VERSION 5.8 ;
BUSBITCHARS "[]" ;
DIVIDERCHAR "/" ;
UNITS
    DATABASE MICRONS 1000 ;
END UNITS

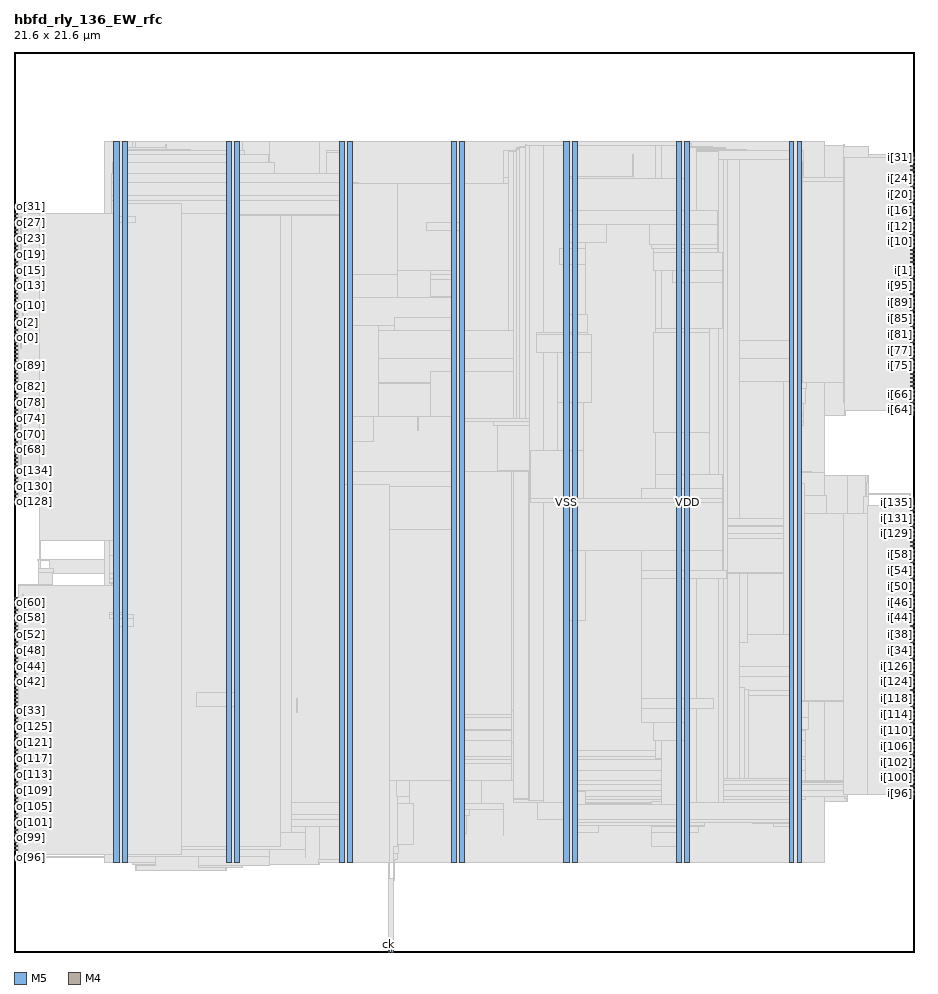
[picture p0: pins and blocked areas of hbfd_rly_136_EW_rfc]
MACRO hbfd_rly_136_EW_rfc
  FOREIGN hbfd_rly_136_EW_rfc 0 0 ;
  CLASS BLOCK ;
  SIZE 21.6 BY 21.6 ;
  PIN ck
    DIRECTION INPUT ;
    USE SIGNAL ;
    PORT
      LAYER M5 ;
        RECT  8.976 0 9 0.084 ;
    END
  END ck
  PIN i[0]
    DIRECTION INPUT ;
    USE SIGNAL ;
    PORT
      LAYER M4 ;
        RECT  21.516 16.08 21.6 16.104 ;
    END
  END i[0]
  PIN i[100]
    DIRECTION INPUT ;
    USE SIGNAL ;
    PORT
      LAYER M4 ;
        RECT  21.516 4.176 21.6 4.2 ;
    END
  END i[100]
  PIN i[101]
    DIRECTION INPUT ;
    USE SIGNAL ;
    PORT
      LAYER M4 ;
        RECT  21.516 4.272 21.6 4.296 ;
    END
  END i[101]
  PIN i[102]
    DIRECTION INPUT ;
    USE SIGNAL ;
    PORT
      LAYER M4 ;
        RECT  21.516 4.368 21.6 4.392 ;
    END
  END i[102]
  PIN i[103]
    DIRECTION INPUT ;
    USE SIGNAL ;
    PORT
      LAYER M4 ;
        RECT  21.516 4.464 21.6 4.488 ;
    END
  END i[103]
  PIN i[104]
    DIRECTION INPUT ;
    USE SIGNAL ;
    PORT
      LAYER M4 ;
        RECT  21.516 4.56 21.6 4.584 ;
    END
  END i[104]
  PIN i[105]
    DIRECTION INPUT ;
    USE SIGNAL ;
    PORT
      LAYER M4 ;
        RECT  21.516 4.656 21.6 4.68 ;
    END
  END i[105]
  PIN i[106]
    DIRECTION INPUT ;
    USE SIGNAL ;
    PORT
      LAYER M4 ;
        RECT  21.516 4.752 21.6 4.776 ;
    END
  END i[106]
  PIN i[107]
    DIRECTION INPUT ;
    USE SIGNAL ;
    PORT
      LAYER M4 ;
        RECT  21.516 4.848 21.6 4.872 ;
    END
  END i[107]
  PIN i[108]
    DIRECTION INPUT ;
    USE SIGNAL ;
    PORT
      LAYER M4 ;
        RECT  21.516 4.944 21.6 4.968 ;
    END
  END i[108]
  PIN i[109]
    DIRECTION INPUT ;
    USE SIGNAL ;
    PORT
      LAYER M4 ;
        RECT  21.516 5.04 21.6 5.064 ;
    END
  END i[109]
  PIN i[10]
    DIRECTION INPUT ;
    USE SIGNAL ;
    PORT
      LAYER M4 ;
        RECT  21.516 17.04 21.6 17.064 ;
    END
  END i[10]
  PIN i[110]
    DIRECTION INPUT ;
    USE SIGNAL ;
    PORT
      LAYER M4 ;
        RECT  21.516 5.136 21.6 5.16 ;
    END
  END i[110]
  PIN i[111]
    DIRECTION INPUT ;
    USE SIGNAL ;
    PORT
      LAYER M4 ;
        RECT  21.516 5.232 21.6 5.256 ;
    END
  END i[111]
  PIN i[112]
    DIRECTION INPUT ;
    USE SIGNAL ;
    PORT
      LAYER M4 ;
        RECT  21.516 5.328 21.6 5.352 ;
    END
  END i[112]
  PIN i[113]
    DIRECTION INPUT ;
    USE SIGNAL ;
    PORT
      LAYER M4 ;
        RECT  21.516 5.424 21.6 5.448 ;
    END
  END i[113]
  PIN i[114]
    DIRECTION INPUT ;
    USE SIGNAL ;
    PORT
      LAYER M4 ;
        RECT  21.516 5.52 21.6 5.544 ;
    END
  END i[114]
  PIN i[115]
    DIRECTION INPUT ;
    USE SIGNAL ;
    PORT
      LAYER M4 ;
        RECT  21.516 5.616 21.6 5.64 ;
    END
  END i[115]
  PIN i[116]
    DIRECTION INPUT ;
    USE SIGNAL ;
    PORT
      LAYER M4 ;
        RECT  21.516 5.712 21.6 5.736 ;
    END
  END i[116]
  PIN i[117]
    DIRECTION INPUT ;
    USE SIGNAL ;
    PORT
      LAYER M4 ;
        RECT  21.516 5.808 21.6 5.832 ;
    END
  END i[117]
  PIN i[118]
    DIRECTION INPUT ;
    USE SIGNAL ;
    PORT
      LAYER M4 ;
        RECT  21.516 5.904 21.6 5.928 ;
    END
  END i[118]
  PIN i[119]
    DIRECTION INPUT ;
    USE SIGNAL ;
    PORT
      LAYER M4 ;
        RECT  21.516 6 21.6 6.024 ;
    END
  END i[119]
  PIN i[11]
    DIRECTION INPUT ;
    USE SIGNAL ;
    PORT
      LAYER M4 ;
        RECT  21.516 17.136 21.6 17.16 ;
    END
  END i[11]
  PIN i[120]
    DIRECTION INPUT ;
    USE SIGNAL ;
    PORT
      LAYER M4 ;
        RECT  21.516 6.096 21.6 6.12 ;
    END
  END i[120]
  PIN i[121]
    DIRECTION INPUT ;
    USE SIGNAL ;
    PORT
      LAYER M4 ;
        RECT  21.516 6.192 21.6 6.216 ;
    END
  END i[121]
  PIN i[122]
    DIRECTION INPUT ;
    USE SIGNAL ;
    PORT
      LAYER M4 ;
        RECT  21.516 6.288 21.6 6.312 ;
    END
  END i[122]
  PIN i[123]
    DIRECTION INPUT ;
    USE SIGNAL ;
    PORT
      LAYER M4 ;
        RECT  21.516 6.384 21.6 6.408 ;
    END
  END i[123]
  PIN i[124]
    DIRECTION INPUT ;
    USE SIGNAL ;
    PORT
      LAYER M4 ;
        RECT  21.516 6.48 21.6 6.504 ;
    END
  END i[124]
  PIN i[125]
    DIRECTION INPUT ;
    USE SIGNAL ;
    PORT
      LAYER M4 ;
        RECT  21.516 6.576 21.6 6.6 ;
    END
  END i[125]
  PIN i[126]
    DIRECTION INPUT ;
    USE SIGNAL ;
    PORT
      LAYER M4 ;
        RECT  21.516 6.672 21.6 6.696 ;
    END
  END i[126]
  PIN i[127]
    DIRECTION INPUT ;
    USE SIGNAL ;
    PORT
      LAYER M4 ;
        RECT  21.516 6.768 21.6 6.792 ;
    END
  END i[127]
  PIN i[128]
    DIRECTION INPUT ;
    USE SIGNAL ;
    PORT
      LAYER M4 ;
        RECT  21.516 9.936 21.6 9.96 ;
    END
  END i[128]
  PIN i[129]
    DIRECTION INPUT ;
    USE SIGNAL ;
    PORT
      LAYER M4 ;
        RECT  21.516 10.032 21.6 10.056 ;
    END
  END i[129]
  PIN i[12]
    DIRECTION INPUT ;
    USE SIGNAL ;
    PORT
      LAYER M4 ;
        RECT  21.516 17.232 21.6 17.256 ;
    END
  END i[12]
  PIN i[130]
    DIRECTION INPUT ;
    USE SIGNAL ;
    PORT
      LAYER M4 ;
        RECT  21.516 10.128 21.6 10.152 ;
    END
  END i[130]
  PIN i[131]
    DIRECTION INPUT ;
    USE SIGNAL ;
    PORT
      LAYER M4 ;
        RECT  21.516 10.224 21.6 10.248 ;
    END
  END i[131]
  PIN i[132]
    DIRECTION INPUT ;
    USE SIGNAL ;
    PORT
      LAYER M4 ;
        RECT  21.516 10.32 21.6 10.344 ;
    END
  END i[132]
  PIN i[133]
    DIRECTION INPUT ;
    USE SIGNAL ;
    PORT
      LAYER M4 ;
        RECT  21.516 10.416 21.6 10.44 ;
    END
  END i[133]
  PIN i[134]
    DIRECTION INPUT ;
    USE SIGNAL ;
    PORT
      LAYER M4 ;
        RECT  21.516 10.512 21.6 10.536 ;
    END
  END i[134]
  PIN i[135]
    DIRECTION INPUT ;
    USE SIGNAL ;
    PORT
      LAYER M4 ;
        RECT  21.516 10.608 21.6 10.632 ;
    END
  END i[135]
  PIN i[13]
    DIRECTION INPUT ;
    USE SIGNAL ;
    PORT
      LAYER M4 ;
        RECT  21.516 17.328 21.6 17.352 ;
    END
  END i[13]
  PIN i[14]
    DIRECTION INPUT ;
    USE SIGNAL ;
    PORT
      LAYER M4 ;
        RECT  21.516 17.424 21.6 17.448 ;
    END
  END i[14]
  PIN i[15]
    DIRECTION INPUT ;
    USE SIGNAL ;
    PORT
      LAYER M4 ;
        RECT  21.516 17.52 21.6 17.544 ;
    END
  END i[15]
  PIN i[16]
    DIRECTION INPUT ;
    USE SIGNAL ;
    PORT
      LAYER M4 ;
        RECT  21.516 17.616 21.6 17.64 ;
    END
  END i[16]
  PIN i[17]
    DIRECTION INPUT ;
    USE SIGNAL ;
    PORT
      LAYER M4 ;
        RECT  21.516 17.712 21.6 17.736 ;
    END
  END i[17]
  PIN i[18]
    DIRECTION INPUT ;
    USE SIGNAL ;
    PORT
      LAYER M4 ;
        RECT  21.516 17.808 21.6 17.832 ;
    END
  END i[18]
  PIN i[19]
    DIRECTION INPUT ;
    USE SIGNAL ;
    PORT
      LAYER M4 ;
        RECT  21.516 17.904 21.6 17.928 ;
    END
  END i[19]
  PIN i[1]
    DIRECTION INPUT ;
    USE SIGNAL ;
    PORT
      LAYER M4 ;
        RECT  21.516 16.176 21.6 16.2 ;
    END
  END i[1]
  PIN i[20]
    DIRECTION INPUT ;
    USE SIGNAL ;
    PORT
      LAYER M4 ;
        RECT  21.516 18 21.6 18.024 ;
    END
  END i[20]
  PIN i[21]
    DIRECTION INPUT ;
    USE SIGNAL ;
    PORT
      LAYER M4 ;
        RECT  21.516 18.096 21.6 18.12 ;
    END
  END i[21]
  PIN i[22]
    DIRECTION INPUT ;
    USE SIGNAL ;
    PORT
      LAYER M4 ;
        RECT  21.516 18.192 21.6 18.216 ;
    END
  END i[22]
  PIN i[23]
    DIRECTION INPUT ;
    USE SIGNAL ;
    PORT
      LAYER M4 ;
        RECT  21.516 18.288 21.6 18.312 ;
    END
  END i[23]
  PIN i[24]
    DIRECTION INPUT ;
    USE SIGNAL ;
    PORT
      LAYER M4 ;
        RECT  21.516 18.384 21.6 18.408 ;
    END
  END i[24]
  PIN i[25]
    DIRECTION INPUT ;
    USE SIGNAL ;
    PORT
      LAYER M4 ;
        RECT  21.516 18.48 21.6 18.504 ;
    END
  END i[25]
  PIN i[26]
    DIRECTION INPUT ;
    USE SIGNAL ;
    PORT
      LAYER M4 ;
        RECT  21.516 18.576 21.6 18.6 ;
    END
  END i[26]
  PIN i[27]
    DIRECTION INPUT ;
    USE SIGNAL ;
    PORT
      LAYER M4 ;
        RECT  21.516 18.672 21.6 18.696 ;
    END
  END i[27]
  PIN i[28]
    DIRECTION INPUT ;
    USE SIGNAL ;
    PORT
      LAYER M4 ;
        RECT  21.516 18.768 21.6 18.792 ;
    END
  END i[28]
  PIN i[29]
    DIRECTION INPUT ;
    USE SIGNAL ;
    PORT
      LAYER M4 ;
        RECT  21.516 18.864 21.6 18.888 ;
    END
  END i[29]
  PIN i[2]
    DIRECTION INPUT ;
    USE SIGNAL ;
    PORT
      LAYER M4 ;
        RECT  21.516 16.272 21.6 16.296 ;
    END
  END i[2]
  PIN i[30]
    DIRECTION INPUT ;
    USE SIGNAL ;
    PORT
      LAYER M4 ;
        RECT  21.516 18.96 21.6 18.984 ;
    END
  END i[30]
  PIN i[31]
    DIRECTION INPUT ;
    USE SIGNAL ;
    PORT
      LAYER M4 ;
        RECT  21.516 19.056 21.6 19.08 ;
    END
  END i[31]
  PIN i[32]
    DIRECTION INPUT ;
    USE SIGNAL ;
    PORT
      LAYER M4 ;
        RECT  21.516 6.864 21.6 6.888 ;
    END
  END i[32]
  PIN i[33]
    DIRECTION INPUT ;
    USE SIGNAL ;
    PORT
      LAYER M4 ;
        RECT  21.516 6.96 21.6 6.984 ;
    END
  END i[33]
  PIN i[34]
    DIRECTION INPUT ;
    USE SIGNAL ;
    PORT
      LAYER M4 ;
        RECT  21.516 7.056 21.6 7.08 ;
    END
  END i[34]
  PIN i[35]
    DIRECTION INPUT ;
    USE SIGNAL ;
    PORT
      LAYER M4 ;
        RECT  21.516 7.152 21.6 7.176 ;
    END
  END i[35]
  PIN i[36]
    DIRECTION INPUT ;
    USE SIGNAL ;
    PORT
      LAYER M4 ;
        RECT  21.516 7.248 21.6 7.272 ;
    END
  END i[36]
  PIN i[37]
    DIRECTION INPUT ;
    USE SIGNAL ;
    PORT
      LAYER M4 ;
        RECT  21.516 7.344 21.6 7.368 ;
    END
  END i[37]
  PIN i[38]
    DIRECTION INPUT ;
    USE SIGNAL ;
    PORT
      LAYER M4 ;
        RECT  21.516 7.44 21.6 7.464 ;
    END
  END i[38]
  PIN i[39]
    DIRECTION INPUT ;
    USE SIGNAL ;
    PORT
      LAYER M4 ;
        RECT  21.516 7.536 21.6 7.56 ;
    END
  END i[39]
  PIN i[3]
    DIRECTION INPUT ;
    USE SIGNAL ;
    PORT
      LAYER M4 ;
        RECT  21.516 16.368 21.6 16.392 ;
    END
  END i[3]
  PIN i[40]
    DIRECTION INPUT ;
    USE SIGNAL ;
    PORT
      LAYER M4 ;
        RECT  21.516 7.632 21.6 7.656 ;
    END
  END i[40]
  PIN i[41]
    DIRECTION INPUT ;
    USE SIGNAL ;
    PORT
      LAYER M4 ;
        RECT  21.516 7.728 21.6 7.752 ;
    END
  END i[41]
  PIN i[42]
    DIRECTION INPUT ;
    USE SIGNAL ;
    PORT
      LAYER M4 ;
        RECT  21.516 7.824 21.6 7.848 ;
    END
  END i[42]
  PIN i[43]
    DIRECTION INPUT ;
    USE SIGNAL ;
    PORT
      LAYER M4 ;
        RECT  21.516 7.92 21.6 7.944 ;
    END
  END i[43]
  PIN i[44]
    DIRECTION INPUT ;
    USE SIGNAL ;
    PORT
      LAYER M4 ;
        RECT  21.516 8.016 21.6 8.04 ;
    END
  END i[44]
  PIN i[45]
    DIRECTION INPUT ;
    USE SIGNAL ;
    PORT
      LAYER M4 ;
        RECT  21.516 8.112 21.6 8.136 ;
    END
  END i[45]
  PIN i[46]
    DIRECTION INPUT ;
    USE SIGNAL ;
    PORT
      LAYER M4 ;
        RECT  21.516 8.208 21.6 8.232 ;
    END
  END i[46]
  PIN i[47]
    DIRECTION INPUT ;
    USE SIGNAL ;
    PORT
      LAYER M4 ;
        RECT  21.516 8.304 21.6 8.328 ;
    END
  END i[47]
  PIN i[48]
    DIRECTION INPUT ;
    USE SIGNAL ;
    PORT
      LAYER M4 ;
        RECT  21.516 8.4 21.6 8.424 ;
    END
  END i[48]
  PIN i[49]
    DIRECTION INPUT ;
    USE SIGNAL ;
    PORT
      LAYER M4 ;
        RECT  21.516 8.496 21.6 8.52 ;
    END
  END i[49]
  PIN i[4]
    DIRECTION INPUT ;
    USE SIGNAL ;
    PORT
      LAYER M4 ;
        RECT  21.516 16.464 21.6 16.488 ;
    END
  END i[4]
  PIN i[50]
    DIRECTION INPUT ;
    USE SIGNAL ;
    PORT
      LAYER M4 ;
        RECT  21.516 8.592 21.6 8.616 ;
    END
  END i[50]
  PIN i[51]
    DIRECTION INPUT ;
    USE SIGNAL ;
    PORT
      LAYER M4 ;
        RECT  21.516 8.688 21.6 8.712 ;
    END
  END i[51]
  PIN i[52]
    DIRECTION INPUT ;
    USE SIGNAL ;
    PORT
      LAYER M4 ;
        RECT  21.516 8.784 21.6 8.808 ;
    END
  END i[52]
  PIN i[53]
    DIRECTION INPUT ;
    USE SIGNAL ;
    PORT
      LAYER M4 ;
        RECT  21.516 8.88 21.6 8.904 ;
    END
  END i[53]
  PIN i[54]
    DIRECTION INPUT ;
    USE SIGNAL ;
    PORT
      LAYER M4 ;
        RECT  21.516 8.976 21.6 9 ;
    END
  END i[54]
  PIN i[55]
    DIRECTION INPUT ;
    USE SIGNAL ;
    PORT
      LAYER M4 ;
        RECT  21.516 9.072 21.6 9.096 ;
    END
  END i[55]
  PIN i[56]
    DIRECTION INPUT ;
    USE SIGNAL ;
    PORT
      LAYER M4 ;
        RECT  21.516 9.168 21.6 9.192 ;
    END
  END i[56]
  PIN i[57]
    DIRECTION INPUT ;
    USE SIGNAL ;
    PORT
      LAYER M4 ;
        RECT  21.516 9.264 21.6 9.288 ;
    END
  END i[57]
  PIN i[58]
    DIRECTION INPUT ;
    USE SIGNAL ;
    PORT
      LAYER M4 ;
        RECT  21.516 9.36 21.6 9.384 ;
    END
  END i[58]
  PIN i[59]
    DIRECTION INPUT ;
    USE SIGNAL ;
    PORT
      LAYER M4 ;
        RECT  21.516 9.456 21.6 9.48 ;
    END
  END i[59]
  PIN i[5]
    DIRECTION INPUT ;
    USE SIGNAL ;
    PORT
      LAYER M4 ;
        RECT  21.516 16.56 21.6 16.584 ;
    END
  END i[5]
  PIN i[60]
    DIRECTION INPUT ;
    USE SIGNAL ;
    PORT
      LAYER M4 ;
        RECT  21.516 9.552 21.6 9.576 ;
    END
  END i[60]
  PIN i[61]
    DIRECTION INPUT ;
    USE SIGNAL ;
    PORT
      LAYER M4 ;
        RECT  21.516 9.648 21.6 9.672 ;
    END
  END i[61]
  PIN i[62]
    DIRECTION INPUT ;
    USE SIGNAL ;
    PORT
      LAYER M4 ;
        RECT  21.516 9.744 21.6 9.768 ;
    END
  END i[62]
  PIN i[63]
    DIRECTION INPUT ;
    USE SIGNAL ;
    PORT
      LAYER M4 ;
        RECT  21.516 9.84 21.6 9.864 ;
    END
  END i[63]
  PIN i[64]
    DIRECTION INPUT ;
    USE SIGNAL ;
    PORT
      LAYER M4 ;
        RECT  21.516 13.008 21.6 13.032 ;
    END
  END i[64]
  PIN i[65]
    DIRECTION INPUT ;
    USE SIGNAL ;
    PORT
      LAYER M4 ;
        RECT  21.516 13.104 21.6 13.128 ;
    END
  END i[65]
  PIN i[66]
    DIRECTION INPUT ;
    USE SIGNAL ;
    PORT
      LAYER M4 ;
        RECT  21.516 13.2 21.6 13.224 ;
    END
  END i[66]
  PIN i[67]
    DIRECTION INPUT ;
    USE SIGNAL ;
    PORT
      LAYER M4 ;
        RECT  21.516 13.296 21.6 13.32 ;
    END
  END i[67]
  PIN i[68]
    DIRECTION INPUT ;
    USE SIGNAL ;
    PORT
      LAYER M4 ;
        RECT  21.516 13.392 21.6 13.416 ;
    END
  END i[68]
  PIN i[69]
    DIRECTION INPUT ;
    USE SIGNAL ;
    PORT
      LAYER M4 ;
        RECT  21.516 13.488 21.6 13.512 ;
    END
  END i[69]
  PIN i[6]
    DIRECTION INPUT ;
    USE SIGNAL ;
    PORT
      LAYER M4 ;
        RECT  21.516 16.656 21.6 16.68 ;
    END
  END i[6]
  PIN i[70]
    DIRECTION INPUT ;
    USE SIGNAL ;
    PORT
      LAYER M4 ;
        RECT  21.516 13.584 21.6 13.608 ;
    END
  END i[70]
  PIN i[71]
    DIRECTION INPUT ;
    USE SIGNAL ;
    PORT
      LAYER M4 ;
        RECT  21.516 13.68 21.6 13.704 ;
    END
  END i[71]
  PIN i[72]
    DIRECTION INPUT ;
    USE SIGNAL ;
    PORT
      LAYER M4 ;
        RECT  21.516 13.776 21.6 13.8 ;
    END
  END i[72]
  PIN i[73]
    DIRECTION INPUT ;
    USE SIGNAL ;
    PORT
      LAYER M4 ;
        RECT  21.516 13.872 21.6 13.896 ;
    END
  END i[73]
  PIN i[74]
    DIRECTION INPUT ;
    USE SIGNAL ;
    PORT
      LAYER M4 ;
        RECT  21.516 13.968 21.6 13.992 ;
    END
  END i[74]
  PIN i[75]
    DIRECTION INPUT ;
    USE SIGNAL ;
    PORT
      LAYER M4 ;
        RECT  21.516 14.064 21.6 14.088 ;
    END
  END i[75]
  PIN i[76]
    DIRECTION INPUT ;
    USE SIGNAL ;
    PORT
      LAYER M4 ;
        RECT  21.516 14.16 21.6 14.184 ;
    END
  END i[76]
  PIN i[77]
    DIRECTION INPUT ;
    USE SIGNAL ;
    PORT
      LAYER M4 ;
        RECT  21.516 14.256 21.6 14.28 ;
    END
  END i[77]
  PIN i[78]
    DIRECTION INPUT ;
    USE SIGNAL ;
    PORT
      LAYER M4 ;
        RECT  21.516 14.352 21.6 14.376 ;
    END
  END i[78]
  PIN i[79]
    DIRECTION INPUT ;
    USE SIGNAL ;
    PORT
      LAYER M4 ;
        RECT  21.516 14.448 21.6 14.472 ;
    END
  END i[79]
  PIN i[7]
    DIRECTION INPUT ;
    USE SIGNAL ;
    PORT
      LAYER M4 ;
        RECT  21.516 16.752 21.6 16.776 ;
    END
  END i[7]
  PIN i[80]
    DIRECTION INPUT ;
    USE SIGNAL ;
    PORT
      LAYER M4 ;
        RECT  21.516 14.544 21.6 14.568 ;
    END
  END i[80]
  PIN i[81]
    DIRECTION INPUT ;
    USE SIGNAL ;
    PORT
      LAYER M4 ;
        RECT  21.516 14.64 21.6 14.664 ;
    END
  END i[81]
  PIN i[82]
    DIRECTION INPUT ;
    USE SIGNAL ;
    PORT
      LAYER M4 ;
        RECT  21.516 14.736 21.6 14.76 ;
    END
  END i[82]
  PIN i[83]
    DIRECTION INPUT ;
    USE SIGNAL ;
    PORT
      LAYER M4 ;
        RECT  21.516 14.832 21.6 14.856 ;
    END
  END i[83]
  PIN i[84]
    DIRECTION INPUT ;
    USE SIGNAL ;
    PORT
      LAYER M4 ;
        RECT  21.516 14.928 21.6 14.952 ;
    END
  END i[84]
  PIN i[85]
    DIRECTION INPUT ;
    USE SIGNAL ;
    PORT
      LAYER M4 ;
        RECT  21.516 15.024 21.6 15.048 ;
    END
  END i[85]
  PIN i[86]
    DIRECTION INPUT ;
    USE SIGNAL ;
    PORT
      LAYER M4 ;
        RECT  21.516 15.12 21.6 15.144 ;
    END
  END i[86]
  PIN i[87]
    DIRECTION INPUT ;
    USE SIGNAL ;
    PORT
      LAYER M4 ;
        RECT  21.516 15.216 21.6 15.24 ;
    END
  END i[87]
  PIN i[88]
    DIRECTION INPUT ;
    USE SIGNAL ;
    PORT
      LAYER M4 ;
        RECT  21.516 15.312 21.6 15.336 ;
    END
  END i[88]
  PIN i[89]
    DIRECTION INPUT ;
    USE SIGNAL ;
    PORT
      LAYER M4 ;
        RECT  21.516 15.408 21.6 15.432 ;
    END
  END i[89]
  PIN i[8]
    DIRECTION INPUT ;
    USE SIGNAL ;
    PORT
      LAYER M4 ;
        RECT  21.516 16.848 21.6 16.872 ;
    END
  END i[8]
  PIN i[90]
    DIRECTION INPUT ;
    USE SIGNAL ;
    PORT
      LAYER M4 ;
        RECT  21.516 15.504 21.6 15.528 ;
    END
  END i[90]
  PIN i[91]
    DIRECTION INPUT ;
    USE SIGNAL ;
    PORT
      LAYER M4 ;
        RECT  21.516 15.6 21.6 15.624 ;
    END
  END i[91]
  PIN i[92]
    DIRECTION INPUT ;
    USE SIGNAL ;
    PORT
      LAYER M4 ;
        RECT  21.516 15.696 21.6 15.72 ;
    END
  END i[92]
  PIN i[93]
    DIRECTION INPUT ;
    USE SIGNAL ;
    PORT
      LAYER M4 ;
        RECT  21.516 15.792 21.6 15.816 ;
    END
  END i[93]
  PIN i[94]
    DIRECTION INPUT ;
    USE SIGNAL ;
    PORT
      LAYER M4 ;
        RECT  21.516 15.888 21.6 15.912 ;
    END
  END i[94]
  PIN i[95]
    DIRECTION INPUT ;
    USE SIGNAL ;
    PORT
      LAYER M4 ;
        RECT  21.516 15.984 21.6 16.008 ;
    END
  END i[95]
  PIN i[96]
    DIRECTION INPUT ;
    USE SIGNAL ;
    PORT
      LAYER M4 ;
        RECT  21.516 3.792 21.6 3.816 ;
    END
  END i[96]
  PIN i[97]
    DIRECTION INPUT ;
    USE SIGNAL ;
    PORT
      LAYER M4 ;
        RECT  21.516 3.888 21.6 3.912 ;
    END
  END i[97]
  PIN i[98]
    DIRECTION INPUT ;
    USE SIGNAL ;
    PORT
      LAYER M4 ;
        RECT  21.516 3.984 21.6 4.008 ;
    END
  END i[98]
  PIN i[99]
    DIRECTION INPUT ;
    USE SIGNAL ;
    PORT
      LAYER M4 ;
        RECT  21.516 4.08 21.6 4.104 ;
    END
  END i[99]
  PIN i[9]
    DIRECTION INPUT ;
    USE SIGNAL ;
    PORT
      LAYER M4 ;
        RECT  21.516 16.944 21.6 16.968 ;
    END
  END i[9]
  PIN o[0]
    DIRECTION OUTPUT ;
    USE SIGNAL ;
    PORT
      LAYER M4 ;
        RECT  0 14.736 0.084 14.76 ;
    END
  END o[0]
  PIN o[100]
    DIRECTION OUTPUT ;
    USE SIGNAL ;
    PORT
      LAYER M4 ;
        RECT  0 2.832 0.084 2.856 ;
    END
  END o[100]
  PIN o[101]
    DIRECTION OUTPUT ;
    USE SIGNAL ;
    PORT
      LAYER M4 ;
        RECT  0 2.928 0.084 2.952 ;
    END
  END o[101]
  PIN o[102]
    DIRECTION OUTPUT ;
    USE SIGNAL ;
    PORT
      LAYER M4 ;
        RECT  0 3.024 0.084 3.048 ;
    END
  END o[102]
  PIN o[103]
    DIRECTION OUTPUT ;
    USE SIGNAL ;
    PORT
      LAYER M4 ;
        RECT  0 3.12 0.084 3.144 ;
    END
  END o[103]
  PIN o[104]
    DIRECTION OUTPUT ;
    USE SIGNAL ;
    PORT
      LAYER M4 ;
        RECT  0 3.216 0.084 3.24 ;
    END
  END o[104]
  PIN o[105]
    DIRECTION OUTPUT ;
    USE SIGNAL ;
    PORT
      LAYER M4 ;
        RECT  0 3.312 0.084 3.336 ;
    END
  END o[105]
  PIN o[106]
    DIRECTION OUTPUT ;
    USE SIGNAL ;
    PORT
      LAYER M4 ;
        RECT  0 3.408 0.084 3.432 ;
    END
  END o[106]
  PIN o[107]
    DIRECTION OUTPUT ;
    USE SIGNAL ;
    PORT
      LAYER M4 ;
        RECT  0 3.504 0.084 3.528 ;
    END
  END o[107]
  PIN o[108]
    DIRECTION OUTPUT ;
    USE SIGNAL ;
    PORT
      LAYER M4 ;
        RECT  0 3.6 0.084 3.624 ;
    END
  END o[108]
  PIN o[109]
    DIRECTION OUTPUT ;
    USE SIGNAL ;
    PORT
      LAYER M4 ;
        RECT  0 3.696 0.084 3.72 ;
    END
  END o[109]
  PIN o[10]
    DIRECTION OUTPUT ;
    USE SIGNAL ;
    PORT
      LAYER M4 ;
        RECT  0 15.696 0.084 15.72 ;
    END
  END o[10]
  PIN o[110]
    DIRECTION OUTPUT ;
    USE SIGNAL ;
    PORT
      LAYER M4 ;
        RECT  0 3.792 0.084 3.816 ;
    END
  END o[110]
  PIN o[111]
    DIRECTION OUTPUT ;
    USE SIGNAL ;
    PORT
      LAYER M4 ;
        RECT  0 3.888 0.084 3.912 ;
    END
  END o[111]
  PIN o[112]
    DIRECTION OUTPUT ;
    USE SIGNAL ;
    PORT
      LAYER M4 ;
        RECT  0 3.984 0.084 4.008 ;
    END
  END o[112]
  PIN o[113]
    DIRECTION OUTPUT ;
    USE SIGNAL ;
    PORT
      LAYER M4 ;
        RECT  0 4.08 0.084 4.104 ;
    END
  END o[113]
  PIN o[114]
    DIRECTION OUTPUT ;
    USE SIGNAL ;
    PORT
      LAYER M4 ;
        RECT  0 4.176 0.084 4.2 ;
    END
  END o[114]
  PIN o[115]
    DIRECTION OUTPUT ;
    USE SIGNAL ;
    PORT
      LAYER M4 ;
        RECT  0 4.272 0.084 4.296 ;
    END
  END o[115]
  PIN o[116]
    DIRECTION OUTPUT ;
    USE SIGNAL ;
    PORT
      LAYER M4 ;
        RECT  0 4.368 0.084 4.392 ;
    END
  END o[116]
  PIN o[117]
    DIRECTION OUTPUT ;
    USE SIGNAL ;
    PORT
      LAYER M4 ;
        RECT  0 4.464 0.084 4.488 ;
    END
  END o[117]
  PIN o[118]
    DIRECTION OUTPUT ;
    USE SIGNAL ;
    PORT
      LAYER M4 ;
        RECT  0 4.56 0.084 4.584 ;
    END
  END o[118]
  PIN o[119]
    DIRECTION OUTPUT ;
    USE SIGNAL ;
    PORT
      LAYER M4 ;
        RECT  0 4.656 0.084 4.68 ;
    END
  END o[119]
  PIN o[11]
    DIRECTION OUTPUT ;
    USE SIGNAL ;
    PORT
      LAYER M4 ;
        RECT  0 15.792 0.084 15.816 ;
    END
  END o[11]
  PIN o[120]
    DIRECTION OUTPUT ;
    USE SIGNAL ;
    PORT
      LAYER M4 ;
        RECT  0 4.752 0.084 4.776 ;
    END
  END o[120]
  PIN o[121]
    DIRECTION OUTPUT ;
    USE SIGNAL ;
    PORT
      LAYER M4 ;
        RECT  0 4.848 0.084 4.872 ;
    END
  END o[121]
  PIN o[122]
    DIRECTION OUTPUT ;
    USE SIGNAL ;
    PORT
      LAYER M4 ;
        RECT  0 4.944 0.084 4.968 ;
    END
  END o[122]
  PIN o[123]
    DIRECTION OUTPUT ;
    USE SIGNAL ;
    PORT
      LAYER M4 ;
        RECT  0 5.04 0.084 5.064 ;
    END
  END o[123]
  PIN o[124]
    DIRECTION OUTPUT ;
    USE SIGNAL ;
    PORT
      LAYER M4 ;
        RECT  0 5.136 0.084 5.16 ;
    END
  END o[124]
  PIN o[125]
    DIRECTION OUTPUT ;
    USE SIGNAL ;
    PORT
      LAYER M4 ;
        RECT  0 5.232 0.084 5.256 ;
    END
  END o[125]
  PIN o[126]
    DIRECTION OUTPUT ;
    USE SIGNAL ;
    PORT
      LAYER M4 ;
        RECT  0 5.328 0.084 5.352 ;
    END
  END o[126]
  PIN o[127]
    DIRECTION OUTPUT ;
    USE SIGNAL ;
    PORT
      LAYER M4 ;
        RECT  0 5.424 0.084 5.448 ;
    END
  END o[127]
  PIN o[128]
    DIRECTION OUTPUT ;
    USE SIGNAL ;
    PORT
      LAYER M4 ;
        RECT  0 10.8 0.084 10.824 ;
    END
  END o[128]
  PIN o[129]
    DIRECTION OUTPUT ;
    USE SIGNAL ;
    PORT
      LAYER M4 ;
        RECT  0 10.896 0.084 10.92 ;
    END
  END o[129]
  PIN o[12]
    DIRECTION OUTPUT ;
    USE SIGNAL ;
    PORT
      LAYER M4 ;
        RECT  0 15.888 0.084 15.912 ;
    END
  END o[12]
  PIN o[130]
    DIRECTION OUTPUT ;
    USE SIGNAL ;
    PORT
      LAYER M4 ;
        RECT  0 10.992 0.084 11.016 ;
    END
  END o[130]
  PIN o[131]
    DIRECTION OUTPUT ;
    USE SIGNAL ;
    PORT
      LAYER M4 ;
        RECT  0 11.088 0.084 11.112 ;
    END
  END o[131]
  PIN o[132]
    DIRECTION OUTPUT ;
    USE SIGNAL ;
    PORT
      LAYER M4 ;
        RECT  0 11.184 0.084 11.208 ;
    END
  END o[132]
  PIN o[133]
    DIRECTION OUTPUT ;
    USE SIGNAL ;
    PORT
      LAYER M4 ;
        RECT  0 11.28 0.084 11.304 ;
    END
  END o[133]
  PIN o[134]
    DIRECTION OUTPUT ;
    USE SIGNAL ;
    PORT
      LAYER M4 ;
        RECT  0 11.376 0.084 11.4 ;
    END
  END o[134]
  PIN o[135]
    DIRECTION OUTPUT ;
    USE SIGNAL ;
    PORT
      LAYER M4 ;
        RECT  0 11.472 0.084 11.496 ;
    END
  END o[135]
  PIN o[13]
    DIRECTION OUTPUT ;
    USE SIGNAL ;
    PORT
      LAYER M4 ;
        RECT  0 15.984 0.084 16.008 ;
    END
  END o[13]
  PIN o[14]
    DIRECTION OUTPUT ;
    USE SIGNAL ;
    PORT
      LAYER M4 ;
        RECT  0 16.08 0.084 16.104 ;
    END
  END o[14]
  PIN o[15]
    DIRECTION OUTPUT ;
    USE SIGNAL ;
    PORT
      LAYER M4 ;
        RECT  0 16.176 0.084 16.2 ;
    END
  END o[15]
  PIN o[16]
    DIRECTION OUTPUT ;
    USE SIGNAL ;
    PORT
      LAYER M4 ;
        RECT  0 16.272 0.084 16.296 ;
    END
  END o[16]
  PIN o[17]
    DIRECTION OUTPUT ;
    USE SIGNAL ;
    PORT
      LAYER M4 ;
        RECT  0 16.368 0.084 16.392 ;
    END
  END o[17]
  PIN o[18]
    DIRECTION OUTPUT ;
    USE SIGNAL ;
    PORT
      LAYER M4 ;
        RECT  0 16.464 0.084 16.488 ;
    END
  END o[18]
  PIN o[19]
    DIRECTION OUTPUT ;
    USE SIGNAL ;
    PORT
      LAYER M4 ;
        RECT  0 16.56 0.084 16.584 ;
    END
  END o[19]
  PIN o[1]
    DIRECTION OUTPUT ;
    USE SIGNAL ;
    PORT
      LAYER M4 ;
        RECT  0 14.832 0.084 14.856 ;
    END
  END o[1]
  PIN o[20]
    DIRECTION OUTPUT ;
    USE SIGNAL ;
    PORT
      LAYER M4 ;
        RECT  0 16.656 0.084 16.68 ;
    END
  END o[20]
  PIN o[21]
    DIRECTION OUTPUT ;
    USE SIGNAL ;
    PORT
      LAYER M4 ;
        RECT  0 16.752 0.084 16.776 ;
    END
  END o[21]
  PIN o[22]
    DIRECTION OUTPUT ;
    USE SIGNAL ;
    PORT
      LAYER M4 ;
        RECT  0 16.848 0.084 16.872 ;
    END
  END o[22]
  PIN o[23]
    DIRECTION OUTPUT ;
    USE SIGNAL ;
    PORT
      LAYER M4 ;
        RECT  0 16.944 0.084 16.968 ;
    END
  END o[23]
  PIN o[24]
    DIRECTION OUTPUT ;
    USE SIGNAL ;
    PORT
      LAYER M4 ;
        RECT  0 17.04 0.084 17.064 ;
    END
  END o[24]
  PIN o[25]
    DIRECTION OUTPUT ;
    USE SIGNAL ;
    PORT
      LAYER M4 ;
        RECT  0 17.136 0.084 17.16 ;
    END
  END o[25]
  PIN o[26]
    DIRECTION OUTPUT ;
    USE SIGNAL ;
    PORT
      LAYER M4 ;
        RECT  0 17.232 0.084 17.256 ;
    END
  END o[26]
  PIN o[27]
    DIRECTION OUTPUT ;
    USE SIGNAL ;
    PORT
      LAYER M4 ;
        RECT  0 17.328 0.084 17.352 ;
    END
  END o[27]
  PIN o[28]
    DIRECTION OUTPUT ;
    USE SIGNAL ;
    PORT
      LAYER M4 ;
        RECT  0 17.424 0.084 17.448 ;
    END
  END o[28]
  PIN o[29]
    DIRECTION OUTPUT ;
    USE SIGNAL ;
    PORT
      LAYER M4 ;
        RECT  0 17.52 0.084 17.544 ;
    END
  END o[29]
  PIN o[2]
    DIRECTION OUTPUT ;
    USE SIGNAL ;
    PORT
      LAYER M4 ;
        RECT  0 14.928 0.084 14.952 ;
    END
  END o[2]
  PIN o[30]
    DIRECTION OUTPUT ;
    USE SIGNAL ;
    PORT
      LAYER M4 ;
        RECT  0 17.616 0.084 17.64 ;
    END
  END o[30]
  PIN o[31]
    DIRECTION OUTPUT ;
    USE SIGNAL ;
    PORT
      LAYER M4 ;
        RECT  0 17.712 0.084 17.736 ;
    END
  END o[31]
  PIN o[32]
    DIRECTION OUTPUT ;
    USE SIGNAL ;
    PORT
      LAYER M4 ;
        RECT  0 5.52 0.084 5.544 ;
    END
  END o[32]
  PIN o[33]
    DIRECTION OUTPUT ;
    USE SIGNAL ;
    PORT
      LAYER M4 ;
        RECT  0 5.616 0.084 5.64 ;
    END
  END o[33]
  PIN o[34]
    DIRECTION OUTPUT ;
    USE SIGNAL ;
    PORT
      LAYER M4 ;
        RECT  0 5.712 0.084 5.736 ;
    END
  END o[34]
  PIN o[35]
    DIRECTION OUTPUT ;
    USE SIGNAL ;
    PORT
      LAYER M4 ;
        RECT  0 5.808 0.084 5.832 ;
    END
  END o[35]
  PIN o[36]
    DIRECTION OUTPUT ;
    USE SIGNAL ;
    PORT
      LAYER M4 ;
        RECT  0 5.904 0.084 5.928 ;
    END
  END o[36]
  PIN o[37]
    DIRECTION OUTPUT ;
    USE SIGNAL ;
    PORT
      LAYER M4 ;
        RECT  0 6 0.084 6.024 ;
    END
  END o[37]
  PIN o[38]
    DIRECTION OUTPUT ;
    USE SIGNAL ;
    PORT
      LAYER M4 ;
        RECT  0 6.096 0.084 6.12 ;
    END
  END o[38]
  PIN o[39]
    DIRECTION OUTPUT ;
    USE SIGNAL ;
    PORT
      LAYER M4 ;
        RECT  0 6.192 0.084 6.216 ;
    END
  END o[39]
  PIN o[3]
    DIRECTION OUTPUT ;
    USE SIGNAL ;
    PORT
      LAYER M4 ;
        RECT  0 15.024 0.084 15.048 ;
    END
  END o[3]
  PIN o[40]
    DIRECTION OUTPUT ;
    USE SIGNAL ;
    PORT
      LAYER M4 ;
        RECT  0 6.288 0.084 6.312 ;
    END
  END o[40]
  PIN o[41]
    DIRECTION OUTPUT ;
    USE SIGNAL ;
    PORT
      LAYER M4 ;
        RECT  0 6.384 0.084 6.408 ;
    END
  END o[41]
  PIN o[42]
    DIRECTION OUTPUT ;
    USE SIGNAL ;
    PORT
      LAYER M4 ;
        RECT  0 6.48 0.084 6.504 ;
    END
  END o[42]
  PIN o[43]
    DIRECTION OUTPUT ;
    USE SIGNAL ;
    PORT
      LAYER M4 ;
        RECT  0 6.576 0.084 6.6 ;
    END
  END o[43]
  PIN o[44]
    DIRECTION OUTPUT ;
    USE SIGNAL ;
    PORT
      LAYER M4 ;
        RECT  0 6.672 0.084 6.696 ;
    END
  END o[44]
  PIN o[45]
    DIRECTION OUTPUT ;
    USE SIGNAL ;
    PORT
      LAYER M4 ;
        RECT  0 6.768 0.084 6.792 ;
    END
  END o[45]
  PIN o[46]
    DIRECTION OUTPUT ;
    USE SIGNAL ;
    PORT
      LAYER M4 ;
        RECT  0 6.864 0.084 6.888 ;
    END
  END o[46]
  PIN o[47]
    DIRECTION OUTPUT ;
    USE SIGNAL ;
    PORT
      LAYER M4 ;
        RECT  0 6.96 0.084 6.984 ;
    END
  END o[47]
  PIN o[48]
    DIRECTION OUTPUT ;
    USE SIGNAL ;
    PORT
      LAYER M4 ;
        RECT  0 7.056 0.084 7.08 ;
    END
  END o[48]
  PIN o[49]
    DIRECTION OUTPUT ;
    USE SIGNAL ;
    PORT
      LAYER M4 ;
        RECT  0 7.152 0.084 7.176 ;
    END
  END o[49]
  PIN o[4]
    DIRECTION OUTPUT ;
    USE SIGNAL ;
    PORT
      LAYER M4 ;
        RECT  0 15.12 0.084 15.144 ;
    END
  END o[4]
  PIN o[50]
    DIRECTION OUTPUT ;
    USE SIGNAL ;
    PORT
      LAYER M4 ;
        RECT  0 7.248 0.084 7.272 ;
    END
  END o[50]
  PIN o[51]
    DIRECTION OUTPUT ;
    USE SIGNAL ;
    PORT
      LAYER M4 ;
        RECT  0 7.344 0.084 7.368 ;
    END
  END o[51]
  PIN o[52]
    DIRECTION OUTPUT ;
    USE SIGNAL ;
    PORT
      LAYER M4 ;
        RECT  0 7.44 0.084 7.464 ;
    END
  END o[52]
  PIN o[53]
    DIRECTION OUTPUT ;
    USE SIGNAL ;
    PORT
      LAYER M4 ;
        RECT  0 7.536 0.084 7.56 ;
    END
  END o[53]
  PIN o[54]
    DIRECTION OUTPUT ;
    USE SIGNAL ;
    PORT
      LAYER M4 ;
        RECT  0 7.632 0.084 7.656 ;
    END
  END o[54]
  PIN o[55]
    DIRECTION OUTPUT ;
    USE SIGNAL ;
    PORT
      LAYER M4 ;
        RECT  0 7.728 0.084 7.752 ;
    END
  END o[55]
  PIN o[56]
    DIRECTION OUTPUT ;
    USE SIGNAL ;
    PORT
      LAYER M4 ;
        RECT  0 7.824 0.084 7.848 ;
    END
  END o[56]
  PIN o[57]
    DIRECTION OUTPUT ;
    USE SIGNAL ;
    PORT
      LAYER M4 ;
        RECT  0 7.92 0.084 7.944 ;
    END
  END o[57]
  PIN o[58]
    DIRECTION OUTPUT ;
    USE SIGNAL ;
    PORT
      LAYER M4 ;
        RECT  0 8.016 0.084 8.04 ;
    END
  END o[58]
  PIN o[59]
    DIRECTION OUTPUT ;
    USE SIGNAL ;
    PORT
      LAYER M4 ;
        RECT  0 8.112 0.084 8.136 ;
    END
  END o[59]
  PIN o[5]
    DIRECTION OUTPUT ;
    USE SIGNAL ;
    PORT
      LAYER M4 ;
        RECT  0 15.216 0.084 15.24 ;
    END
  END o[5]
  PIN o[60]
    DIRECTION OUTPUT ;
    USE SIGNAL ;
    PORT
      LAYER M4 ;
        RECT  0 8.208 0.084 8.232 ;
    END
  END o[60]
  PIN o[61]
    DIRECTION OUTPUT ;
    USE SIGNAL ;
    PORT
      LAYER M4 ;
        RECT  0 8.304 0.084 8.328 ;
    END
  END o[61]
  PIN o[62]
    DIRECTION OUTPUT ;
    USE SIGNAL ;
    PORT
      LAYER M4 ;
        RECT  0 8.4 0.084 8.424 ;
    END
  END o[62]
  PIN o[63]
    DIRECTION OUTPUT ;
    USE SIGNAL ;
    PORT
      LAYER M4 ;
        RECT  0 8.496 0.084 8.52 ;
    END
  END o[63]
  PIN o[64]
    DIRECTION OUTPUT ;
    USE SIGNAL ;
    PORT
      LAYER M4 ;
        RECT  0 11.664 0.084 11.688 ;
    END
  END o[64]
  PIN o[65]
    DIRECTION OUTPUT ;
    USE SIGNAL ;
    PORT
      LAYER M4 ;
        RECT  0 11.76 0.084 11.784 ;
    END
  END o[65]
  PIN o[66]
    DIRECTION OUTPUT ;
    USE SIGNAL ;
    PORT
      LAYER M4 ;
        RECT  0 11.856 0.084 11.88 ;
    END
  END o[66]
  PIN o[67]
    DIRECTION OUTPUT ;
    USE SIGNAL ;
    PORT
      LAYER M4 ;
        RECT  0 11.952 0.084 11.976 ;
    END
  END o[67]
  PIN o[68]
    DIRECTION OUTPUT ;
    USE SIGNAL ;
    PORT
      LAYER M4 ;
        RECT  0 12.048 0.084 12.072 ;
    END
  END o[68]
  PIN o[69]
    DIRECTION OUTPUT ;
    USE SIGNAL ;
    PORT
      LAYER M4 ;
        RECT  0 12.144 0.084 12.168 ;
    END
  END o[69]
  PIN o[6]
    DIRECTION OUTPUT ;
    USE SIGNAL ;
    PORT
      LAYER M4 ;
        RECT  0 15.312 0.084 15.336 ;
    END
  END o[6]
  PIN o[70]
    DIRECTION OUTPUT ;
    USE SIGNAL ;
    PORT
      LAYER M4 ;
        RECT  0 12.24 0.084 12.264 ;
    END
  END o[70]
  PIN o[71]
    DIRECTION OUTPUT ;
    USE SIGNAL ;
    PORT
      LAYER M4 ;
        RECT  0 12.336 0.084 12.36 ;
    END
  END o[71]
  PIN o[72]
    DIRECTION OUTPUT ;
    USE SIGNAL ;
    PORT
      LAYER M4 ;
        RECT  0 12.432 0.084 12.456 ;
    END
  END o[72]
  PIN o[73]
    DIRECTION OUTPUT ;
    USE SIGNAL ;
    PORT
      LAYER M4 ;
        RECT  0 12.528 0.084 12.552 ;
    END
  END o[73]
  PIN o[74]
    DIRECTION OUTPUT ;
    USE SIGNAL ;
    PORT
      LAYER M4 ;
        RECT  0 12.624 0.084 12.648 ;
    END
  END o[74]
  PIN o[75]
    DIRECTION OUTPUT ;
    USE SIGNAL ;
    PORT
      LAYER M4 ;
        RECT  0 12.72 0.084 12.744 ;
    END
  END o[75]
  PIN o[76]
    DIRECTION OUTPUT ;
    USE SIGNAL ;
    PORT
      LAYER M4 ;
        RECT  0 12.816 0.084 12.84 ;
    END
  END o[76]
  PIN o[77]
    DIRECTION OUTPUT ;
    USE SIGNAL ;
    PORT
      LAYER M4 ;
        RECT  0 12.912 0.084 12.936 ;
    END
  END o[77]
  PIN o[78]
    DIRECTION OUTPUT ;
    USE SIGNAL ;
    PORT
      LAYER M4 ;
        RECT  0 13.008 0.084 13.032 ;
    END
  END o[78]
  PIN o[79]
    DIRECTION OUTPUT ;
    USE SIGNAL ;
    PORT
      LAYER M4 ;
        RECT  0 13.104 0.084 13.128 ;
    END
  END o[79]
  PIN o[7]
    DIRECTION OUTPUT ;
    USE SIGNAL ;
    PORT
      LAYER M4 ;
        RECT  0 15.408 0.084 15.432 ;
    END
  END o[7]
  PIN o[80]
    DIRECTION OUTPUT ;
    USE SIGNAL ;
    PORT
      LAYER M4 ;
        RECT  0 13.2 0.084 13.224 ;
    END
  END o[80]
  PIN o[81]
    DIRECTION OUTPUT ;
    USE SIGNAL ;
    PORT
      LAYER M4 ;
        RECT  0 13.296 0.084 13.32 ;
    END
  END o[81]
  PIN o[82]
    DIRECTION OUTPUT ;
    USE SIGNAL ;
    PORT
      LAYER M4 ;
        RECT  0 13.392 0.084 13.416 ;
    END
  END o[82]
  PIN o[83]
    DIRECTION OUTPUT ;
    USE SIGNAL ;
    PORT
      LAYER M4 ;
        RECT  0 13.488 0.084 13.512 ;
    END
  END o[83]
  PIN o[84]
    DIRECTION OUTPUT ;
    USE SIGNAL ;
    PORT
      LAYER M4 ;
        RECT  0 13.584 0.084 13.608 ;
    END
  END o[84]
  PIN o[85]
    DIRECTION OUTPUT ;
    USE SIGNAL ;
    PORT
      LAYER M4 ;
        RECT  0 13.68 0.084 13.704 ;
    END
  END o[85]
  PIN o[86]
    DIRECTION OUTPUT ;
    USE SIGNAL ;
    PORT
      LAYER M4 ;
        RECT  0 13.776 0.084 13.8 ;
    END
  END o[86]
  PIN o[87]
    DIRECTION OUTPUT ;
    USE SIGNAL ;
    PORT
      LAYER M4 ;
        RECT  0 13.872 0.084 13.896 ;
    END
  END o[87]
  PIN o[88]
    DIRECTION OUTPUT ;
    USE SIGNAL ;
    PORT
      LAYER M4 ;
        RECT  0 13.968 0.084 13.992 ;
    END
  END o[88]
  PIN o[89]
    DIRECTION OUTPUT ;
    USE SIGNAL ;
    PORT
      LAYER M4 ;
        RECT  0 14.064 0.084 14.088 ;
    END
  END o[89]
  PIN o[8]
    DIRECTION OUTPUT ;
    USE SIGNAL ;
    PORT
      LAYER M4 ;
        RECT  0 15.504 0.084 15.528 ;
    END
  END o[8]
  PIN o[90]
    DIRECTION OUTPUT ;
    USE SIGNAL ;
    PORT
      LAYER M4 ;
        RECT  0 14.16 0.084 14.184 ;
    END
  END o[90]
  PIN o[91]
    DIRECTION OUTPUT ;
    USE SIGNAL ;
    PORT
      LAYER M4 ;
        RECT  0 14.256 0.084 14.28 ;
    END
  END o[91]
  PIN o[92]
    DIRECTION OUTPUT ;
    USE SIGNAL ;
    PORT
      LAYER M4 ;
        RECT  0 14.352 0.084 14.376 ;
    END
  END o[92]
  PIN o[93]
    DIRECTION OUTPUT ;
    USE SIGNAL ;
    PORT
      LAYER M4 ;
        RECT  0 14.448 0.084 14.472 ;
    END
  END o[93]
  PIN o[94]
    DIRECTION OUTPUT ;
    USE SIGNAL ;
    PORT
      LAYER M4 ;
        RECT  0 14.544 0.084 14.568 ;
    END
  END o[94]
  PIN o[95]
    DIRECTION OUTPUT ;
    USE SIGNAL ;
    PORT
      LAYER M4 ;
        RECT  0 14.64 0.084 14.664 ;
    END
  END o[95]
  PIN o[96]
    DIRECTION OUTPUT ;
    USE SIGNAL ;
    PORT
      LAYER M4 ;
        RECT  0 2.448 0.084 2.472 ;
    END
  END o[96]
  PIN o[97]
    DIRECTION OUTPUT ;
    USE SIGNAL ;
    PORT
      LAYER M4 ;
        RECT  0 2.544 0.084 2.568 ;
    END
  END o[97]
  PIN o[98]
    DIRECTION OUTPUT ;
    USE SIGNAL ;
    PORT
      LAYER M4 ;
        RECT  0 2.64 0.084 2.664 ;
    END
  END o[98]
  PIN o[99]
    DIRECTION OUTPUT ;
    USE SIGNAL ;
    PORT
      LAYER M4 ;
        RECT  0 2.736 0.084 2.76 ;
    END
  END o[99]
  PIN o[9]
    DIRECTION OUTPUT ;
    USE SIGNAL ;
    PORT
      LAYER M4 ;
        RECT  0 15.6 0.084 15.624 ;
    END
  END o[9]
  PIN rfi
    DIRECTION INPUT ;
    USE SIGNAL ;
    PORT
      LAYER M4 ;
        RECT  21.516 10.704 21.6 10.728 ;
    END
  END rfi
  PIN rfo
    DIRECTION OUTPUT ;
    USE SIGNAL ;
    PORT
      LAYER M4 ;
        RECT  0 11.568 0.084 11.592 ;
    END
  END rfo
  PIN rs
    DIRECTION INPUT ;
    USE SIGNAL ;
    PORT
      LAYER M5 ;
        RECT  9.072 0 9.096 0.084 ;
    END
  END rs
  PIN VDD
    DIRECTION INOUT ;
    USE POWER ;
    PORT
      LAYER M5 ;
        RECT  18.792 2.151 18.912 19.449 ;
        RECT  16.092 2.151 16.212 19.449 ;
        RECT  13.392 2.151 13.512 19.449 ;
        RECT  10.692 2.151 10.812 19.449 ;
        RECT  7.992 2.151 8.112 19.449 ;
        RECT  5.292 2.151 5.412 19.449 ;
        RECT  2.592 2.151 2.712 19.449 ;
    END
  END VDD
  PIN VSS
    DIRECTION INOUT ;
    USE GROUND ;
    PORT
      LAYER M5 ;
        RECT  18.6 2.137 18.72 19.463 ;
        RECT  15.9 2.137 16.02 19.463 ;
        RECT  13.2 2.137 13.32 19.463 ;
        RECT  10.5 2.137 10.62 19.463 ;
        RECT  7.8 2.137 7.92 19.463 ;
        RECT  5.1 2.137 5.22 19.463 ;
        RECT  2.4 2.137 2.52 19.463 ;
    END
  END VSS
  OBS
    LAYER RVTN ;
     RECT  2.16 2.16 19.44 2.295 ;
     RECT  2.16 2.565 19.44 2.835 ;
     RECT  2.16 3.105 19.44 3.375 ;
     RECT  2.16 3.645 19.44 3.915 ;
     RECT  2.16 4.185 19.44 4.455 ;
     RECT  2.16 4.725 19.44 4.995 ;
     RECT  2.16 5.265 19.44 5.535 ;
     RECT  2.16 5.805 19.44 6.075 ;
     RECT  2.16 6.345 19.44 6.615 ;
     RECT  2.16 6.885 19.44 7.155 ;
     RECT  2.16 7.425 19.44 7.695 ;
     RECT  2.16 7.965 19.44 8.235 ;
     RECT  2.16 8.505 19.44 8.775 ;
     RECT  2.16 9.045 19.44 9.315 ;
     RECT  2.16 9.585 19.44 9.855 ;
     RECT  2.16 10.125 19.44 10.395 ;
     RECT  2.16 10.665 19.44 10.935 ;
     RECT  2.16 11.205 19.44 11.475 ;
     RECT  2.16 11.745 19.44 12.015 ;
     RECT  2.16 12.285 19.44 12.555 ;
     RECT  2.16 12.825 19.44 13.095 ;
     RECT  2.16 13.365 19.44 13.635 ;
     RECT  2.16 13.905 19.44 14.175 ;
     RECT  2.16 14.445 19.44 14.715 ;
     RECT  2.16 14.985 19.44 15.255 ;
     RECT  2.16 15.525 19.44 15.795 ;
     RECT  2.16 16.065 19.44 16.335 ;
     RECT  2.16 16.605 19.44 16.875 ;
     RECT  2.16 17.145 19.44 17.415 ;
     RECT  2.16 17.685 19.44 17.955 ;
     RECT  2.16 18.225 19.44 18.495 ;
     RECT  2.16 18.765 19.44 19.035 ;
     RECT  2.16 19.305 19.44 19.44 ;
    LAYER RVTP ;
     RECT  2.16 2.295 19.44 2.565 ;
     RECT  2.16 2.835 19.44 3.105 ;
     RECT  2.16 3.375 19.44 3.645 ;
     RECT  2.16 3.915 19.44 4.185 ;
     RECT  2.16 4.455 19.44 4.725 ;
     RECT  2.16 4.995 19.44 5.265 ;
     RECT  2.16 5.535 19.44 5.805 ;
     RECT  2.16 6.075 19.44 6.345 ;
     RECT  2.16 6.615 19.44 6.885 ;
     RECT  2.16 7.155 19.44 7.425 ;
     RECT  2.16 7.695 19.44 7.965 ;
     RECT  2.16 8.235 19.44 8.505 ;
     RECT  2.16 8.775 19.44 9.045 ;
     RECT  2.16 9.315 19.44 9.585 ;
     RECT  2.16 9.855 19.44 10.125 ;
     RECT  2.16 10.395 19.44 10.665 ;
     RECT  2.16 10.935 19.44 11.205 ;
     RECT  2.16 11.475 19.44 11.745 ;
     RECT  2.16 12.015 19.44 12.285 ;
     RECT  2.16 12.555 19.44 12.825 ;
     RECT  2.16 13.095 19.44 13.365 ;
     RECT  2.16 13.635 19.44 13.905 ;
     RECT  2.16 14.175 19.44 14.445 ;
     RECT  2.16 14.715 19.44 14.985 ;
     RECT  2.16 15.255 19.44 15.525 ;
     RECT  2.16 15.795 19.44 16.065 ;
     RECT  2.16 16.335 19.44 16.605 ;
     RECT  2.16 16.875 19.44 17.145 ;
     RECT  2.16 17.415 19.44 17.685 ;
     RECT  2.16 17.955 19.44 18.225 ;
     RECT  2.16 18.495 19.44 18.765 ;
     RECT  2.16 19.035 19.44 19.305 ;
    LAYER M1 ;
     RECT  2.16 2.151 19.44 19.449 ;
    LAYER M2 ;
     RECT  0.103 5.508 0.175 5.526 ;
     RECT  0.103 3.186 0.203 3.204 ;
     RECT  0.103 4.266 0.203 4.284 ;
     RECT  0.175 5.436 0.203 5.526 ;
     RECT  0.103 11.826 0.203 11.844 ;
     RECT  0.103 13.446 0.203 13.896 ;
     RECT  0.103 14.958 0.203 15.354 ;
     RECT  0.103 16.146 0.203 16.326 ;
     RECT  0.203 5.436 0.211 5.454 ;
     RECT  0.203 13.572 0.239 13.824 ;
     RECT  0.203 14.958 0.239 15.246 ;
     RECT  0.203 16.308 0.239 16.326 ;
     RECT  0.211 4.536 0.275 5.454 ;
     RECT  0.211 7.236 0.347 7.254 ;
     RECT  0.239 15.228 0.383 15.246 ;
     RECT  0.499 11.214 0.535 11.232 ;
     RECT  0.463 11.988 0.535 12.006 ;
     RECT  0.247 8.55 0.599 8.568 ;
     RECT  0.239 13.806 0.743 13.824 ;
     RECT  0.571 9.396 0.859 9.414 ;
     RECT  0.275 4.536 1.111 4.914 ;
     RECT  0.535 10.71 1.111 11.232 ;
     RECT  0.535 11.988 1.111 12.654 ;
     RECT  1.111 10.71 1.139 12.654 ;
     RECT  0.535 2.268 2.16 2.286 ;
     RECT  0.499 3.15 2.16 3.168 ;
     RECT  1.111 4.266 2.16 4.914 ;
     RECT  0.859 9.09 2.16 9.414 ;
     RECT  1.139 10.71 2.16 11.502 ;
     RECT  1.139 12.636 2.16 12.654 ;
     RECT  2.16 2.151 2.839 19.449 ;
     RECT  2.839 2.106 2.911 19.449 ;
     RECT  2.911 1.962 5.099 19.449 ;
     RECT  5.099 2.034 5.495 19.449 ;
     RECT  5.495 2.07 6.143 19.449 ;
     RECT  6.143 2.106 7.331 19.449 ;
     RECT  7.331 2.151 19.44 19.449 ;
     RECT  19.44 3.618 19.463 11.502 ;
     RECT  19.44 12.87 19.931 19.368 ;
     RECT  19.931 12.87 19.967 15.354 ;
     RECT  19.931 16.146 19.967 19.332 ;
     RECT  19.463 3.618 20.003 11.43 ;
     RECT  19.967 12.996 20.039 15.354 ;
     RECT  20.003 3.888 20.435 11.43 ;
     RECT  20.039 13.338 20.435 15.354 ;
     RECT  20.435 5.238 20.507 9.684 ;
     RECT  20.435 10.44 20.507 11.43 ;
     RECT  20.435 13.446 20.507 15.354 ;
     RECT  19.967 16.308 20.507 19.332 ;
     RECT  20.435 3.888 20.543 3.906 ;
     RECT  20.507 13.446 20.543 13.662 ;
     RECT  20.507 14.418 20.543 15.354 ;
     RECT  20.543 14.418 20.579 14.778 ;
     RECT  20.543 13.446 20.615 13.464 ;
     RECT  20.507 5.274 21.371 9.684 ;
     RECT  20.579 14.418 21.443 14.589 ;
     RECT  21.371 5.274 21.479 6.102 ;
     RECT  21.371 6.894 21.479 9.684 ;
     RECT  20.507 16.956 21.479 17.784 ;
     RECT  20.507 19.08 21.479 19.134 ;
     RECT  21.479 5.31 21.515 5.328 ;
     RECT  21.479 6.084 21.515 6.102 ;
     RECT  21.479 6.894 21.515 8.262 ;
     RECT  21.479 9.324 21.515 9.684 ;
     RECT  20.507 10.98 21.515 10.998 ;
     RECT  21.443 14.571 21.515 14.589 ;
     RECT  21.479 16.956 21.515 16.974 ;
     RECT  21.479 17.766 21.515 17.784 ;
     RECT  21.479 19.08 21.515 19.098 ;
    LAYER M3 ;
     RECT  5.076 1.957 5.094 2.029 ;
     RECT  2.916 1.957 2.934 2.065 ;
     RECT  4.428 2.029 5.49 2.065 ;
     RECT  2.916 2.065 3.402 2.101 ;
     RECT  2.844 2.101 3.402 2.143 ;
     RECT  7.308 2.101 7.326 2.143 ;
     RECT  7.308 2.143 7.905 2.219 ;
     RECT  9.108 1.723 9.126 2.227 ;
     RECT  2.415 2.143 3.402 2.299 ;
     RECT  4.428 2.065 6.138 2.299 ;
     RECT  0.54 2.263 0.558 2.347 ;
     RECT  9.108 2.227 9.198 2.371 ;
     RECT  7.815 2.219 7.905 2.413 ;
     RECT  10.515 2.143 10.605 2.413 ;
     RECT  13.215 2.143 13.305 2.413 ;
     RECT  15.915 2.143 16.005 2.413 ;
     RECT  18.615 2.143 18.705 2.413 ;
     RECT  2.415 2.299 6.138 2.461 ;
     RECT  6.984 2.263 7.002 2.461 ;
     RECT  9.108 2.371 9.234 2.525 ;
     RECT  15.915 2.413 16.197 2.533 ;
     RECT  9.216 2.525 9.234 2.569 ;
     RECT  10.515 2.413 10.797 2.839 ;
     RECT  2.415 2.461 7.002 2.875 ;
     RECT  13.215 2.413 13.497 2.875 ;
     RECT  15.3 2.533 16.197 2.875 ;
     RECT  2.376 2.875 7.002 3.001 ;
     RECT  7.815 2.413 8.097 3.001 ;
     RECT  15.3 2.875 16.434 3.001 ;
     RECT  18.615 2.413 18.897 3.001 ;
     RECT  13.215 2.875 14.022 3.037 ;
     RECT  15.3 3.001 16.578 3.037 ;
     RECT  18.216 3.001 18.897 3.073 ;
     RECT  13.215 3.037 16.578 3.109 ;
     RECT  17.712 3.073 18.897 3.109 ;
     RECT  0.108 2.347 0.558 3.149 ;
     RECT  2.376 3.001 8.097 3.181 ;
     RECT  13.215 3.109 18.897 3.181 ;
     RECT  0.108 3.149 0.522 3.212 ;
     RECT  10.515 2.839 10.854 3.271 ;
     RECT  2.304 3.181 8.097 3.299 ;
     RECT  10.515 3.271 10.926 3.415 ;
     RECT  11.736 2.803 11.754 3.415 ;
     RECT  9.216 2.569 9.594 3.569 ;
     RECT  10.515 3.415 11.754 3.569 ;
     RECT  12.564 3.181 18.897 3.577 ;
     RECT  11.988 3.577 18.897 3.649 ;
     RECT  19.98 3.613 19.998 3.685 ;
     RECT  9.216 3.569 9.486 3.721 ;
     RECT  11.988 3.649 18.99 3.721 ;
     RECT  19.944 3.685 19.998 3.721 ;
     RECT  11.988 3.721 19.998 3.883 ;
     RECT  11.988 3.883 20.538 4.013 ;
     RECT  2.34 3.299 8.097 4.081 ;
     RECT  2.304 4.081 8.097 4.109 ;
     RECT  11.988 4.013 20.43 4.109 ;
     RECT  2.304 4.109 7.038 4.157 ;
     RECT  0.144 3.212 0.522 4.171 ;
     RECT  10.515 3.569 11.214 4.189 ;
     RECT  0.144 4.171 0.63 4.261 ;
     RECT  9.18 3.721 9.486 4.261 ;
     RECT  7.776 4.109 8.097 4.289 ;
     RECT  0.108 4.261 1.134 4.301 ;
     RECT  10.296 4.189 11.214 4.351 ;
     RECT  11.988 4.109 18.99 4.351 ;
     RECT  7.815 4.289 8.097 4.387 ;
     RECT  9.144 4.261 9.486 4.621 ;
     RECT  10.296 4.351 18.99 4.621 ;
     RECT  7.815 4.387 8.154 4.693 ;
     RECT  9.144 4.621 18.99 4.693 ;
     RECT  0.144 4.301 1.134 4.733 ;
     RECT  0.18 4.733 1.134 4.877 ;
     RECT  21.492 4.843 21.51 4.939 ;
     RECT  2.34 4.157 7.038 5.035 ;
     RECT  2.34 5.035 7.074 5.071 ;
     RECT  7.815 4.693 18.99 5.071 ;
     RECT  21.456 4.939 21.51 5.131 ;
     RECT  0.18 4.877 0.558 5.165 ;
     RECT  19.908 4.109 20.43 5.224 ;
     RECT  2.34 5.071 18.99 5.305 ;
     RECT  2.304 5.305 18.99 5.341 ;
     RECT  0.18 5.165 0.27 5.5 ;
     RECT  21.42 5.131 21.51 5.611 ;
     RECT  2.304 5.341 19.062 5.639 ;
     RECT  0.108 5.5 0.27 5.645 ;
     RECT  0.216 5.645 0.27 5.741 ;
     RECT  21.384 5.611 21.51 5.8 ;
     RECT  19.908 5.224 20.502 5.899 ;
     RECT  9.144 5.639 19.062 6.007 ;
     RECT  19.908 5.899 20.538 6.007 ;
     RECT  21.348 5.8 21.51 6.179 ;
     RECT  9.144 6.007 20.538 6.269 ;
     RECT  9.18 6.269 20.538 6.605 ;
     RECT  0.144 6.475 0.162 6.619 ;
     RECT  0.9 6.187 0.918 6.619 ;
     RECT  0.144 6.619 0.918 6.667 ;
     RECT  9.18 6.605 20.502 6.845 ;
     RECT  2.304 5.639 8.097 7.088 ;
     RECT  21.492 6.179 21.51 7.618 ;
     RECT  9.72 6.845 20.502 7.723 ;
     RECT  2.34 7.088 8.097 7.861 ;
     RECT  2.34 7.861 8.154 7.933 ;
     RECT  9.684 7.723 20.502 7.961 ;
     RECT  2.34 7.933 8.622 8.041 ;
     RECT  10.515 7.961 20.502 8.231 ;
     RECT  10.515 8.231 20.43 8.501 ;
     RECT  2.34 8.041 8.73 8.545 ;
     RECT  9.684 7.961 9.738 8.545 ;
     RECT  2.34 8.545 9.738 8.699 ;
     RECT  21.456 7.618 21.51 8.779 ;
     RECT  0.108 6.667 0.918 8.813 ;
     RECT  2.34 8.699 8.982 8.851 ;
     RECT  2.304 8.851 8.982 8.879 ;
     RECT  2.304 8.879 6.318 8.969 ;
     RECT  21.42 8.779 21.51 8.971 ;
     RECT  10.515 8.501 19.926 9.011 ;
     RECT  7.092 8.879 8.982 9.041 ;
     RECT  2.304 8.969 6.138 9.077 ;
     RECT  0.576 8.813 0.918 9.112 ;
     RECT  11.7 9.011 19.926 9.113 ;
     RECT  0.576 9.112 0.954 9.194 ;
     RECT  19.872 9.113 19.926 9.259 ;
     RECT  9.72 8.699 9.738 9.283 ;
     RECT  10.515 9.011 10.854 9.283 ;
     RECT  9.72 9.283 10.854 9.311 ;
     RECT  21.384 8.971 21.51 9.311 ;
     RECT  0.576 9.194 0.63 9.419 ;
     RECT  2.304 9.077 6.066 9.509 ;
     RECT  21.456 9.311 21.51 9.581 ;
     RECT  9.792 9.311 10.854 9.617 ;
     RECT  7.092 9.041 8.73 9.851 ;
     RECT  7.092 9.851 8.097 9.859 ;
     RECT  6.804 9.859 8.097 9.883 ;
     RECT  0.612 9.419 0.63 9.917 ;
     RECT  19.872 9.259 20.502 9.923 ;
     RECT  10.296 9.617 10.854 9.931 ;
     RECT  11.7 9.113 19.134 9.931 ;
     RECT  2.304 9.509 5.922 10.049 ;
     RECT  10.296 9.931 19.134 10.049 ;
     RECT  2.304 10.049 5.814 10.085 ;
     RECT  10.515 10.049 19.134 10.201 ;
     RECT  10.515 10.201 19.494 10.229 ;
     RECT  0.108 10.699 0.126 10.705 ;
     RECT  6.696 9.883 8.097 10.741 ;
     RECT  0.108 10.705 0.558 10.829 ;
     RECT  20.376 9.923 20.502 10.931 ;
     RECT  2.304 10.085 4.302 10.939 ;
     RECT  5.115 10.085 5.814 10.939 ;
     RECT  11.7 10.229 19.494 10.967 ;
     RECT  21.492 9.581 21.51 11.003 ;
     RECT  20.448 10.931 20.502 11.273 ;
     RECT  10.515 10.229 10.962 11.309 ;
     RECT  20.484 11.273 20.502 11.435 ;
     RECT  0.144 10.829 0.558 11.479 ;
     RECT  2.304 10.939 5.814 11.479 ;
     RECT  6.552 10.741 8.097 11.479 ;
     RECT  11.7 10.967 19.458 11.507 ;
     RECT  11.7 11.507 19.134 11.543 ;
     RECT  11.7 11.543 18.897 11.551 ;
     RECT  0.144 11.479 1.134 11.563 ;
     RECT  0.108 11.563 1.134 11.852 ;
     RECT  0.18 11.852 1.134 12.011 ;
     RECT  2.304 11.479 8.097 12.253 ;
     RECT  11.592 11.551 18.897 12.631 ;
     RECT  10.515 11.309 10.797 12.721 ;
     RECT  11.52 12.631 18.954 12.721 ;
     RECT  0.18 12.011 0.558 12.859 ;
     RECT  9.684 12.523 9.702 12.901 ;
     RECT  10.515 12.721 18.954 12.901 ;
     RECT  19.944 12.865 19.962 12.991 ;
     RECT  9.684 12.901 18.954 13.171 ;
     RECT  0.18 12.859 0.594 13.195 ;
     RECT  19.944 12.991 20.034 13.195 ;
     RECT  19.908 13.195 20.034 13.291 ;
     RECT  2.304 12.253 8.622 13.387 ;
     RECT  19.908 13.291 20.43 13.441 ;
     RECT  2.304 13.387 8.658 13.531 ;
     RECT  9.684 13.171 18.99 13.531 ;
     RECT  2.304 13.531 19.026 13.675 ;
     RECT  19.908 13.441 20.61 13.675 ;
     RECT  0.108 13.195 0.594 13.771 ;
     RECT  0.108 13.771 0.666 13.801 ;
     RECT  0.108 13.801 0.738 13.853 ;
     RECT  0.108 13.853 0.666 13.997 ;
     RECT  0.108 13.997 0.342 14.093 ;
     RECT  2.304 13.675 20.61 14.243 ;
     RECT  21.42 14.155 21.438 14.441 ;
     RECT  21.492 14.443 21.51 14.594 ;
     RECT  0.144 14.093 0.342 14.923 ;
     RECT  2.304 14.243 19.134 15.019 ;
     RECT  19.872 14.243 20.61 15.019 ;
     RECT  0.108 14.923 0.342 15.223 ;
     RECT  0.108 15.223 0.378 15.341 ;
     RECT  2.304 15.019 20.61 15.719 ;
     RECT  10.008 15.719 20.61 15.725 ;
     RECT  10.008 15.725 20.502 16.133 ;
     RECT  10.008 16.133 19.134 16.259 ;
     RECT  0.108 15.341 0.306 16.331 ;
     RECT  2.304 15.719 9.198 16.609 ;
     RECT  10.008 16.259 10.926 16.609 ;
     RECT  2.304 16.609 10.926 16.799 ;
     RECT  11.736 16.259 19.134 16.799 ;
     RECT  19.872 16.133 20.502 16.879 ;
     RECT  2.304 16.799 8.334 17.105 ;
     RECT  2.304 17.105 8.097 17.221 ;
     RECT  2.268 17.221 8.097 17.261 ;
     RECT  9.144 16.799 10.926 17.311 ;
     RECT  11.736 16.799 18.954 17.311 ;
     RECT  0.144 16.331 0.306 17.357 ;
     RECT  0.288 17.357 0.306 17.405 ;
     RECT  21.492 16.747 21.51 17.419 ;
     RECT  9.144 17.311 18.954 17.617 ;
     RECT  19.836 16.879 20.502 17.617 ;
     RECT  0.324 17.515 0.342 17.645 ;
     RECT  21.456 17.419 21.51 17.681 ;
     RECT  2.304 17.261 8.097 17.693 ;
     RECT  21.492 17.681 21.51 17.789 ;
     RECT  9.144 17.617 20.502 17.879 ;
     RECT  9.684 17.879 20.502 18.023 ;
     RECT  2.34 17.693 8.097 18.031 ;
     RECT  2.34 18.031 8.586 18.149 ;
     RECT  9.756 18.023 20.502 18.221 ;
     RECT  10.116 18.221 20.502 18.269 ;
     RECT  10.116 18.269 10.797 18.419 ;
     RECT  2.34 18.149 8.262 18.461 ;
     RECT  11.736 18.269 20.502 18.599 ;
     RECT  2.34 18.461 8.097 18.689 ;
     RECT  21.492 18.859 21.51 18.955 ;
     RECT  2.376 18.689 6.246 18.959 ;
     RECT  21.456 18.955 21.51 19.103 ;
     RECT  2.415 18.959 6.102 19.139 ;
     RECT  21.456 19.103 21.474 19.139 ;
     RECT  7.488 18.689 8.097 19.187 ;
     RECT  10.515 18.419 10.797 19.187 ;
     RECT  2.415 19.139 5.526 19.229 ;
     RECT  7.488 19.187 7.905 19.229 ;
     RECT  11.736 18.599 18.954 19.229 ;
     RECT  11.88 19.229 17.586 19.235 ;
     RECT  2.415 19.229 4.23 19.265 ;
     RECT  12.024 19.235 17.586 19.265 ;
     RECT  12.06 19.265 17.082 19.277 ;
     RECT  2.415 19.265 3.654 19.301 ;
     RECT  12.06 19.277 14.094 19.301 ;
     RECT  15.156 19.277 17.082 19.301 ;
     RECT  12.132 19.301 12.294 19.325 ;
     RECT  13.215 19.301 14.058 19.325 ;
     RECT  15.156 19.301 15.174 19.337 ;
     RECT  15.915 19.301 16.758 19.337 ;
     RECT  19.908 18.599 20.502 19.337 ;
     RECT  3.636 19.301 3.654 19.373 ;
     RECT  12.276 19.325 12.294 19.373 ;
     RECT  19.908 19.337 19.926 19.373 ;
     RECT  15.915 19.337 16.254 19.409 ;
     RECT  2.415 19.301 2.505 19.457 ;
     RECT  5.115 19.229 5.205 19.457 ;
     RECT  7.815 19.229 7.905 19.457 ;
     RECT  10.515 19.187 10.605 19.457 ;
     RECT  13.215 19.325 13.305 19.457 ;
     RECT  15.915 19.409 16.005 19.457 ;
     RECT  18.615 19.229 18.705 19.457 ;
    LAYER M4 ;
     RECT  0.06 2.448 0.097 8.52 ;
     RECT  0.06 10.8 0.097 17.736 ;
     RECT  0.097 10.704 0.601 17.736 ;
     RECT  0.097 2.352 2.408 8.808 ;
     RECT  0.601 9.888 2.408 17.736 ;
     RECT  2.408 2.148 2.512 19.452 ;
     RECT  2.512 2.352 2.704 19.182 ;
     RECT  2.704 2.352 4.025 17.976 ;
     RECT  4.025 2.544 5.108 17.736 ;
     RECT  5.108 2.148 5.212 19.452 ;
     RECT  5.212 2.418 5.404 19.182 ;
     RECT  5.404 2.544 6.401 17.688 ;
     RECT  6.401 2.88 6.653 17.688 ;
     RECT  6.653 3.6 7.808 17.688 ;
     RECT  7.808 2.148 7.912 19.452 ;
     RECT  7.912 2.418 8.104 19.182 ;
     RECT  8.104 12.864 8.741 15.048 ;
     RECT  8.741 14.928 9.133 15.048 ;
     RECT  9.053 1.728 9.137 1.752 ;
     RECT  8.104 16.272 9.209 18.456 ;
     RECT  8.741 12.864 9.997 13.656 ;
     RECT  8.104 4.128 10.508 10.152 ;
     RECT  8.104 11.184 10.508 11.544 ;
     RECT  9.997 12.864 10.508 13.944 ;
     RECT  9.133 14.928 10.508 15.24 ;
     RECT  9.209 16.368 10.508 18.456 ;
     RECT  10.508 2.148 10.612 19.452 ;
     RECT  10.612 2.418 10.804 19.182 ;
     RECT  10.804 14.928 11.869 18.456 ;
     RECT  10.804 4.128 11.941 4.536 ;
     RECT  10.804 5.712 11.941 11.544 ;
     RECT  11.941 4.128 11.977 11.544 ;
     RECT  10.804 12.816 11.977 13.944 ;
     RECT  11.869 14.928 11.977 19.224 ;
     RECT  11.977 12.816 12.049 19.224 ;
     RECT  12.049 12.816 12.121 19.272 ;
     RECT  12.121 12.816 12.265 19.32 ;
     RECT  11.977 3.696 12.337 11.544 ;
     RECT  12.337 3.648 12.373 11.544 ;
     RECT  12.265 12.816 12.373 19.368 ;
     RECT  12.373 3.648 12.697 19.368 ;
     RECT  12.697 3.6 13.208 19.368 ;
     RECT  13.208 2.148 13.312 19.452 ;
     RECT  13.312 2.418 13.504 19.368 ;
     RECT  13.504 3.552 13.709 3.864 ;
     RECT  13.709 3.552 15.289 3.576 ;
     RECT  13.504 4.848 15.397 19.368 ;
     RECT  15.289 3.552 15.541 3.624 ;
     RECT  15.397 4.656 15.541 19.368 ;
     RECT  15.541 3.552 15.908 19.368 ;
     RECT  15.908 2.148 16.012 19.452 ;
     RECT  16.012 2.418 16.204 19.32 ;
     RECT  16.204 3.6 16.373 19.32 ;
     RECT  16.373 3.6 16.913 19.224 ;
     RECT  16.913 3.6 17.021 19.032 ;
     RECT  17.021 4.176 17.129 19.032 ;
     RECT  17.129 4.176 17.417 9.096 ;
     RECT  17.129 10.416 17.417 19.032 ;
     RECT  17.417 4.176 17.525 6.36 ;
     RECT  17.417 7.44 17.597 9.096 ;
     RECT  17.525 4.176 17.633 6.312 ;
     RECT  17.597 7.632 18.457 9.096 ;
     RECT  17.417 10.416 18.457 13.704 ;
     RECT  17.633 4.176 18.608 6.168 ;
     RECT  18.457 7.632 18.608 13.704 ;
     RECT  17.417 14.688 18.608 19.032 ;
     RECT  18.608 2.148 18.712 19.452 ;
     RECT  18.712 2.418 18.904 19.182 ;
     RECT  18.904 13.68 18.929 18.984 ;
     RECT  18.904 6.048 18.965 11.256 ;
     RECT  18.904 4.08 19.897 4.104 ;
     RECT  18.965 6.048 19.897 10.536 ;
     RECT  18.929 13.68 19.897 18.504 ;
     RECT  19.897 13.2 19.933 19.08 ;
     RECT  19.897 3.792 20.473 10.536 ;
     RECT  20.473 3.792 21.564 10.728 ;
     RECT  19.933 13.008 21.564 19.08 ;
    LAYER M5 ;
     RECT  8.976 0.016 9.096 1.763 ;
     RECT  2.4 2.137 2.52 2.151 ;
     RECT  5.1 2.137 5.22 2.151 ;
     RECT  7.8 2.137 7.92 2.151 ;
     RECT  8.976 1.763 9 2.151 ;
     RECT  10.5 2.137 10.62 2.151 ;
     RECT  13.2 2.137 13.32 2.151 ;
     RECT  15.9 2.137 16.02 2.151 ;
     RECT  18.6 2.137 18.72 2.151 ;
     RECT  15.9 2.151 16.212 5.077 ;
     RECT  15.36 5.077 16.212 5.509 ;
     RECT  11.952 5.029 11.976 5.795 ;
     RECT  15.072 5.509 16.212 5.845 ;
     RECT  5.1 2.151 5.412 5.893 ;
     RECT  6.768 5.749 6.792 6.083 ;
     RECT  15.072 5.845 16.776 6.083 ;
     RECT  4.368 5.893 5.412 6.227 ;
     RECT  2.4 2.151 2.712 7.813 ;
     RECT  13.2 2.151 13.512 7.957 ;
     RECT  2.4 7.813 2.856 8.005 ;
     RECT  2.304 8.005 2.856 8.099 ;
     RECT  2.304 8.099 2.712 8.147 ;
     RECT  0.192 8.437 0.216 8.579 ;
     RECT  15.072 6.083 16.212 8.965 ;
     RECT  15.072 8.965 17.112 9.155 ;
     RECT  13.2 7.957 13.704 9.637 ;
     RECT  15.072 9.155 17.016 9.637 ;
     RECT  13.2 9.637 17.016 10.789 ;
     RECT  12.384 10.789 17.016 10.883 ;
     RECT  15.072 10.883 17.016 11.123 ;
     RECT  7.8 2.151 9 11.219 ;
     RECT  15.408 11.123 17.016 11.459 ;
     RECT  12.384 10.883 13.656 12.035 ;
     RECT  15.408 11.459 16.68 12.469 ;
     RECT  0.144 11.701 0.168 12.995 ;
     RECT  13.056 12.035 13.656 13.189 ;
     RECT  13.056 13.189 13.848 14.389 ;
     RECT  0.144 14.485 0.168 14.675 ;
     RECT  12.528 14.389 13.848 14.819 ;
     RECT  12.528 14.819 13.752 14.867 ;
     RECT  15.36 12.469 16.68 14.867 ;
     RECT  15.408 14.867 16.68 14.963 ;
     RECT  15.9 14.963 16.68 14.965 ;
     RECT  13.2 14.867 13.752 15.299 ;
     RECT  0.192 15.157 0.216 15.347 ;
     RECT  15.9 14.965 17.016 16.069 ;
     RECT  15.792 16.069 17.016 16.357 ;
     RECT  13.2 15.299 13.704 16.501 ;
     RECT  15.36 16.357 17.016 16.787 ;
     RECT  13.104 16.501 13.704 16.883 ;
     RECT  15.36 16.787 16.872 16.885 ;
     RECT  15.312 16.885 16.872 16.981 ;
     RECT  13.2 16.883 13.704 17.029 ;
     RECT  10.5 2.151 10.812 17.317 ;
     RECT  13.2 17.029 14.232 17.461 ;
     RECT  15.264 16.981 16.872 17.461 ;
     RECT  9.888 17.317 10.812 17.507 ;
     RECT  2.4 8.147 2.712 17.509 ;
     RECT  0.144 16.837 0.168 17.651 ;
     RECT  2.4 17.509 2.904 17.651 ;
     RECT  13.2 17.461 16.872 17.795 ;
     RECT  13.2 17.795 16.212 18.563 ;
     RECT  13.2 18.563 14.856 18.611 ;
     RECT  14.832 18.611 14.856 19.139 ;
     RECT  2.4 17.651 2.712 19.449 ;
     RECT  5.1 6.227 5.412 19.449 ;
     RECT  7.8 11.219 8.112 19.449 ;
     RECT  10.5 17.507 10.812 19.449 ;
     RECT  13.2 18.611 13.512 19.449 ;
     RECT  15.9 18.563 16.212 19.449 ;
     RECT  18.6 2.151 18.912 19.449 ;
     RECT  2.4 19.449 2.52 19.463 ;
     RECT  5.1 19.449 5.22 19.463 ;
     RECT  7.8 19.449 7.92 19.463 ;
     RECT  10.5 19.449 10.62 19.463 ;
     RECT  13.2 19.449 13.32 19.463 ;
     RECT  15.9 19.449 16.02 19.463 ;
     RECT  18.6 19.449 18.72 19.463 ;
  END
END hbfd_rly_136_EW_rfc
END LIBRARY
